VERSION 5.7 ;
  NOWIREEXTENSIONATPIN ON ;
  DIVIDERCHAR "/" ;
  BUSBITCHARS "[]" ;
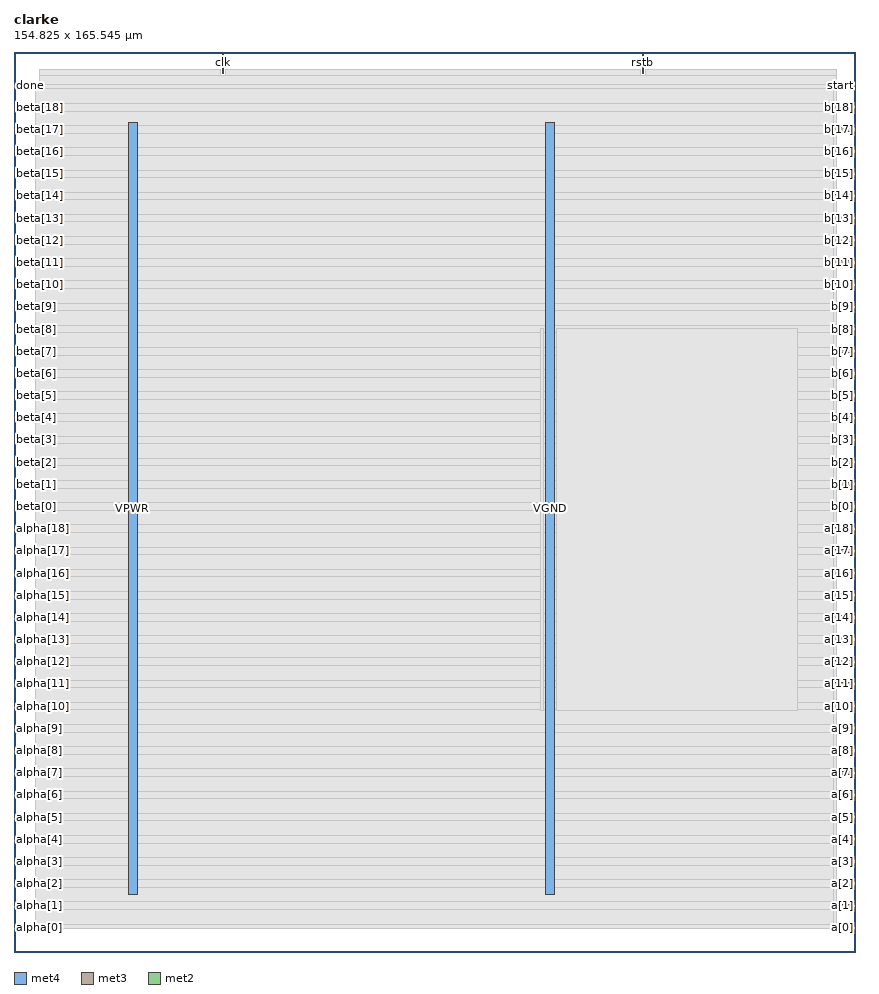
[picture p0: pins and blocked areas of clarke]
MACRO clarke
  CLASS BLOCK ;
  FOREIGN clarke ;
  ORIGIN 0.000 0.000 ;
  SIZE 154.825 BY 165.545 ;
  PIN VGND
    DIRECTION INOUT ;
    USE GROUND ;
    PORT
      LAYER met4 ;
        RECT 97.840 10.640 99.440 152.560 ;
    END
  END VGND
  PIN VPWR
    DIRECTION INOUT ;
    USE POWER ;
    PORT
      LAYER met4 ;
        RECT 21.040 10.640 22.640 152.560 ;
    END
  END VPWR
  PIN a[0]
    DIRECTION INPUT ;
    USE SIGNAL ;
    ANTENNAGATEAREA 0.213000 ;
    PORT
      LAYER met3 ;
        RECT 150.825 4.120 154.825 4.720 ;
    END
  END a[0]
  PIN a[10]
    DIRECTION INPUT ;
    USE SIGNAL ;
    ANTENNAGATEAREA 0.196500 ;
    PORT
      LAYER met3 ;
        RECT 150.825 44.920 154.825 45.520 ;
    END
  END a[10]
  PIN a[11]
    DIRECTION INPUT ;
    USE SIGNAL ;
    ANTENNAGATEAREA 0.213000 ;
    PORT
      LAYER met3 ;
        RECT 150.825 49.000 154.825 49.600 ;
    END
  END a[11]
  PIN a[12]
    DIRECTION INPUT ;
    USE SIGNAL ;
    ANTENNAGATEAREA 0.213000 ;
    PORT
      LAYER met3 ;
        RECT 150.825 53.080 154.825 53.680 ;
    END
  END a[12]
  PIN a[13]
    DIRECTION INPUT ;
    USE SIGNAL ;
    ANTENNAGATEAREA 0.159000 ;
    PORT
      LAYER met3 ;
        RECT 150.825 57.160 154.825 57.760 ;
    END
  END a[13]
  PIN a[14]
    DIRECTION INPUT ;
    USE SIGNAL ;
    ANTENNAGATEAREA 0.495000 ;
    PORT
      LAYER met3 ;
        RECT 150.825 61.240 154.825 61.840 ;
    END
  END a[14]
  PIN a[15]
    DIRECTION INPUT ;
    USE SIGNAL ;
    ANTENNAGATEAREA 0.196500 ;
    PORT
      LAYER met3 ;
        RECT 150.825 65.320 154.825 65.920 ;
    END
  END a[15]
  PIN a[16]
    DIRECTION INPUT ;
    USE SIGNAL ;
    ANTENNAGATEAREA 0.213000 ;
    PORT
      LAYER met3 ;
        RECT 150.825 69.400 154.825 70.000 ;
    END
  END a[16]
  PIN a[17]
    DIRECTION INPUT ;
    USE SIGNAL ;
    ANTENNAGATEAREA 0.159000 ;
    PORT
      LAYER met3 ;
        RECT 150.825 73.480 154.825 74.080 ;
    END
  END a[17]
  PIN a[18]
    DIRECTION INPUT ;
    USE SIGNAL ;
    ANTENNAGATEAREA 0.213000 ;
    PORT
      LAYER met3 ;
        RECT 150.825 77.560 154.825 78.160 ;
    END
  END a[18]
  PIN a[1]
    DIRECTION INPUT ;
    USE SIGNAL ;
    ANTENNAGATEAREA 0.213000 ;
    PORT
      LAYER met3 ;
        RECT 150.825 8.200 154.825 8.800 ;
    END
  END a[1]
  PIN a[2]
    DIRECTION INPUT ;
    USE SIGNAL ;
    ANTENNAGATEAREA 0.196500 ;
    PORT
      LAYER met3 ;
        RECT 150.825 12.280 154.825 12.880 ;
    END
  END a[2]
  PIN a[3]
    DIRECTION INPUT ;
    USE SIGNAL ;
    ANTENNAGATEAREA 0.213000 ;
    PORT
      LAYER met3 ;
        RECT 150.825 16.360 154.825 16.960 ;
    END
  END a[3]
  PIN a[4]
    DIRECTION INPUT ;
    USE SIGNAL ;
    ANTENNAGATEAREA 0.196500 ;
    PORT
      LAYER met3 ;
        RECT 150.825 20.440 154.825 21.040 ;
    END
  END a[4]
  PIN a[5]
    DIRECTION INPUT ;
    USE SIGNAL ;
    ANTENNAGATEAREA 0.196500 ;
    PORT
      LAYER met3 ;
        RECT 150.825 24.520 154.825 25.120 ;
    END
  END a[5]
  PIN a[6]
    DIRECTION INPUT ;
    USE SIGNAL ;
    ANTENNAGATEAREA 0.213000 ;
    PORT
      LAYER met3 ;
        RECT 150.825 28.600 154.825 29.200 ;
    END
  END a[6]
  PIN a[7]
    DIRECTION INPUT ;
    USE SIGNAL ;
    ANTENNAGATEAREA 0.213000 ;
    PORT
      LAYER met3 ;
        RECT 150.825 32.680 154.825 33.280 ;
    END
  END a[7]
  PIN a[8]
    DIRECTION INPUT ;
    USE SIGNAL ;
    ANTENNAGATEAREA 0.196500 ;
    PORT
      LAYER met3 ;
        RECT 150.825 36.760 154.825 37.360 ;
    END
  END a[8]
  PIN a[9]
    DIRECTION INPUT ;
    USE SIGNAL ;
    ANTENNAGATEAREA 0.213000 ;
    PORT
      LAYER met3 ;
        RECT 150.825 40.840 154.825 41.440 ;
    END
  END a[9]
  PIN alpha[0]
    DIRECTION OUTPUT ;
    USE SIGNAL ;
    ANTENNADIFFAREA 0.795200 ;
    PORT
      LAYER met3 ;
        RECT 0.000 4.120 4.000 4.720 ;
    END
  END alpha[0]
  PIN alpha[10]
    DIRECTION OUTPUT ;
    USE SIGNAL ;
    ANTENNADIFFAREA 0.795200 ;
    PORT
      LAYER met3 ;
        RECT 0.000 44.920 4.000 45.520 ;
    END
  END alpha[10]
  PIN alpha[11]
    DIRECTION OUTPUT ;
    USE SIGNAL ;
    ANTENNADIFFAREA 0.795200 ;
    PORT
      LAYER met3 ;
        RECT 0.000 49.000 4.000 49.600 ;
    END
  END alpha[11]
  PIN alpha[12]
    DIRECTION OUTPUT ;
    USE SIGNAL ;
    ANTENNADIFFAREA 0.795200 ;
    PORT
      LAYER met3 ;
        RECT 0.000 53.080 4.000 53.680 ;
    END
  END alpha[12]
  PIN alpha[13]
    DIRECTION OUTPUT ;
    USE SIGNAL ;
    ANTENNADIFFAREA 0.795200 ;
    PORT
      LAYER met3 ;
        RECT 0.000 57.160 4.000 57.760 ;
    END
  END alpha[13]
  PIN alpha[14]
    DIRECTION OUTPUT ;
    USE SIGNAL ;
    ANTENNADIFFAREA 0.795200 ;
    PORT
      LAYER met3 ;
        RECT 0.000 61.240 4.000 61.840 ;
    END
  END alpha[14]
  PIN alpha[15]
    DIRECTION OUTPUT ;
    USE SIGNAL ;
    ANTENNADIFFAREA 0.795200 ;
    PORT
      LAYER met3 ;
        RECT 0.000 65.320 4.000 65.920 ;
    END
  END alpha[15]
  PIN alpha[16]
    DIRECTION OUTPUT ;
    USE SIGNAL ;
    ANTENNADIFFAREA 0.795200 ;
    PORT
      LAYER met3 ;
        RECT 0.000 69.400 4.000 70.000 ;
    END
  END alpha[16]
  PIN alpha[17]
    DIRECTION OUTPUT ;
    USE SIGNAL ;
    ANTENNADIFFAREA 0.795200 ;
    PORT
      LAYER met3 ;
        RECT 0.000 73.480 4.000 74.080 ;
    END
  END alpha[17]
  PIN alpha[18]
    DIRECTION OUTPUT ;
    USE SIGNAL ;
    ANTENNADIFFAREA 0.795200 ;
    PORT
      LAYER met3 ;
        RECT 0.000 77.560 4.000 78.160 ;
    END
  END alpha[18]
  PIN alpha[1]
    DIRECTION OUTPUT ;
    USE SIGNAL ;
    ANTENNADIFFAREA 0.795200 ;
    PORT
      LAYER met3 ;
        RECT 0.000 8.200 4.000 8.800 ;
    END
  END alpha[1]
  PIN alpha[2]
    DIRECTION OUTPUT ;
    USE SIGNAL ;
    ANTENNADIFFAREA 0.795200 ;
    PORT
      LAYER met3 ;
        RECT 0.000 12.280 4.000 12.880 ;
    END
  END alpha[2]
  PIN alpha[3]
    DIRECTION OUTPUT ;
    USE SIGNAL ;
    ANTENNADIFFAREA 0.795200 ;
    PORT
      LAYER met3 ;
        RECT 0.000 16.360 4.000 16.960 ;
    END
  END alpha[3]
  PIN alpha[4]
    DIRECTION OUTPUT ;
    USE SIGNAL ;
    ANTENNADIFFAREA 0.795200 ;
    PORT
      LAYER met3 ;
        RECT 0.000 20.440 4.000 21.040 ;
    END
  END alpha[4]
  PIN alpha[5]
    DIRECTION OUTPUT ;
    USE SIGNAL ;
    ANTENNADIFFAREA 0.795200 ;
    PORT
      LAYER met3 ;
        RECT 0.000 24.520 4.000 25.120 ;
    END
  END alpha[5]
  PIN alpha[6]
    DIRECTION OUTPUT ;
    USE SIGNAL ;
    ANTENNADIFFAREA 0.795200 ;
    PORT
      LAYER met3 ;
        RECT 0.000 28.600 4.000 29.200 ;
    END
  END alpha[6]
  PIN alpha[7]
    DIRECTION OUTPUT ;
    USE SIGNAL ;
    ANTENNADIFFAREA 0.795200 ;
    PORT
      LAYER met3 ;
        RECT 0.000 32.680 4.000 33.280 ;
    END
  END alpha[7]
  PIN alpha[8]
    DIRECTION OUTPUT ;
    USE SIGNAL ;
    ANTENNADIFFAREA 0.795200 ;
    PORT
      LAYER met3 ;
        RECT 0.000 36.760 4.000 37.360 ;
    END
  END alpha[8]
  PIN alpha[9]
    DIRECTION OUTPUT ;
    USE SIGNAL ;
    ANTENNADIFFAREA 0.795200 ;
    PORT
      LAYER met3 ;
        RECT 0.000 40.840 4.000 41.440 ;
    END
  END alpha[9]
  PIN b[0]
    DIRECTION INPUT ;
    USE SIGNAL ;
    ANTENNAGATEAREA 0.126000 ;
    PORT
      LAYER met3 ;
        RECT 150.825 81.640 154.825 82.240 ;
    END
  END b[0]
  PIN b[10]
    DIRECTION INPUT ;
    USE SIGNAL ;
    ANTENNAGATEAREA 0.213000 ;
    PORT
      LAYER met3 ;
        RECT 150.825 122.440 154.825 123.040 ;
    END
  END b[10]
  PIN b[11]
    DIRECTION INPUT ;
    USE SIGNAL ;
    ANTENNAGATEAREA 0.196500 ;
    PORT
      LAYER met3 ;
        RECT 150.825 126.520 154.825 127.120 ;
    END
  END b[11]
  PIN b[12]
    DIRECTION INPUT ;
    USE SIGNAL ;
    ANTENNAGATEAREA 0.196500 ;
    PORT
      LAYER met3 ;
        RECT 150.825 130.600 154.825 131.200 ;
    END
  END b[12]
  PIN b[13]
    DIRECTION INPUT ;
    USE SIGNAL ;
    ANTENNAGATEAREA 0.196500 ;
    PORT
      LAYER met3 ;
        RECT 150.825 134.680 154.825 135.280 ;
    END
  END b[13]
  PIN b[14]
    DIRECTION INPUT ;
    USE SIGNAL ;
    ANTENNAGATEAREA 0.196500 ;
    PORT
      LAYER met3 ;
        RECT 150.825 138.760 154.825 139.360 ;
    END
  END b[14]
  PIN b[15]
    DIRECTION INPUT ;
    USE SIGNAL ;
    ANTENNAGATEAREA 0.196500 ;
    PORT
      LAYER met3 ;
        RECT 150.825 142.840 154.825 143.440 ;
    END
  END b[15]
  PIN b[16]
    DIRECTION INPUT ;
    USE SIGNAL ;
    ANTENNAGATEAREA 0.196500 ;
    PORT
      LAYER met3 ;
        RECT 150.825 146.920 154.825 147.520 ;
    END
  END b[16]
  PIN b[17]
    DIRECTION INPUT ;
    USE SIGNAL ;
    ANTENNAGATEAREA 0.196500 ;
    PORT
      LAYER met3 ;
        RECT 150.825 151.000 154.825 151.600 ;
    END
  END b[17]
  PIN b[18]
    DIRECTION INPUT ;
    USE SIGNAL ;
    ANTENNAGATEAREA 0.196500 ;
    PORT
      LAYER met3 ;
        RECT 150.825 155.080 154.825 155.680 ;
    END
  END b[18]
  PIN b[1]
    DIRECTION INPUT ;
    USE SIGNAL ;
    ANTENNAGATEAREA 0.196500 ;
    PORT
      LAYER met3 ;
        RECT 150.825 85.720 154.825 86.320 ;
    END
  END b[1]
  PIN b[2]
    DIRECTION INPUT ;
    USE SIGNAL ;
    ANTENNAGATEAREA 0.196500 ;
    PORT
      LAYER met3 ;
        RECT 150.825 89.800 154.825 90.400 ;
    END
  END b[2]
  PIN b[3]
    DIRECTION INPUT ;
    USE SIGNAL ;
    ANTENNAGATEAREA 0.196500 ;
    PORT
      LAYER met3 ;
        RECT 150.825 93.880 154.825 94.480 ;
    END
  END b[3]
  PIN b[4]
    DIRECTION INPUT ;
    USE SIGNAL ;
    ANTENNAGATEAREA 0.196500 ;
    PORT
      LAYER met3 ;
        RECT 150.825 97.960 154.825 98.560 ;
    END
  END b[4]
  PIN b[5]
    DIRECTION INPUT ;
    USE SIGNAL ;
    ANTENNAGATEAREA 0.196500 ;
    PORT
      LAYER met3 ;
        RECT 150.825 102.040 154.825 102.640 ;
    END
  END b[5]
  PIN b[6]
    DIRECTION INPUT ;
    USE SIGNAL ;
    ANTENNAGATEAREA 0.495000 ;
    PORT
      LAYER met3 ;
        RECT 150.825 106.120 154.825 106.720 ;
    END
  END b[6]
  PIN b[7]
    DIRECTION INPUT ;
    USE SIGNAL ;
    ANTENNAGATEAREA 0.196500 ;
    PORT
      LAYER met3 ;
        RECT 150.825 110.200 154.825 110.800 ;
    END
  END b[7]
  PIN b[8]
    DIRECTION INPUT ;
    USE SIGNAL ;
    ANTENNAGATEAREA 0.196500 ;
    PORT
      LAYER met3 ;
        RECT 150.825 114.280 154.825 114.880 ;
    END
  END b[8]
  PIN b[9]
    DIRECTION INPUT ;
    USE SIGNAL ;
    ANTENNAGATEAREA 0.196500 ;
    PORT
      LAYER met3 ;
        RECT 150.825 118.360 154.825 118.960 ;
    END
  END b[9]
  PIN beta[0]
    DIRECTION OUTPUT ;
    USE SIGNAL ;
    ANTENNADIFFAREA 0.795200 ;
    PORT
      LAYER met3 ;
        RECT 0.000 81.640 4.000 82.240 ;
    END
  END beta[0]
  PIN beta[10]
    DIRECTION OUTPUT ;
    USE SIGNAL ;
    ANTENNADIFFAREA 0.795200 ;
    PORT
      LAYER met3 ;
        RECT 0.000 122.440 4.000 123.040 ;
    END
  END beta[10]
  PIN beta[11]
    DIRECTION OUTPUT ;
    USE SIGNAL ;
    ANTENNADIFFAREA 0.795200 ;
    PORT
      LAYER met3 ;
        RECT 0.000 126.520 4.000 127.120 ;
    END
  END beta[11]
  PIN beta[12]
    DIRECTION OUTPUT ;
    USE SIGNAL ;
    ANTENNADIFFAREA 0.795200 ;
    PORT
      LAYER met3 ;
        RECT 0.000 130.600 4.000 131.200 ;
    END
  END beta[12]
  PIN beta[13]
    DIRECTION OUTPUT ;
    USE SIGNAL ;
    ANTENNADIFFAREA 0.795200 ;
    PORT
      LAYER met3 ;
        RECT 0.000 134.680 4.000 135.280 ;
    END
  END beta[13]
  PIN beta[14]
    DIRECTION OUTPUT ;
    USE SIGNAL ;
    ANTENNADIFFAREA 0.795200 ;
    PORT
      LAYER met3 ;
        RECT 0.000 138.760 4.000 139.360 ;
    END
  END beta[14]
  PIN beta[15]
    DIRECTION OUTPUT ;
    USE SIGNAL ;
    ANTENNADIFFAREA 0.795200 ;
    PORT
      LAYER met3 ;
        RECT 0.000 142.840 4.000 143.440 ;
    END
  END beta[15]
  PIN beta[16]
    DIRECTION OUTPUT ;
    USE SIGNAL ;
    ANTENNADIFFAREA 0.795200 ;
    PORT
      LAYER met3 ;
        RECT 0.000 146.920 4.000 147.520 ;
    END
  END beta[16]
  PIN beta[17]
    DIRECTION OUTPUT ;
    USE SIGNAL ;
    ANTENNADIFFAREA 0.795200 ;
    PORT
      LAYER met3 ;
        RECT 0.000 151.000 4.000 151.600 ;
    END
  END beta[17]
  PIN beta[18]
    DIRECTION OUTPUT ;
    USE SIGNAL ;
    ANTENNADIFFAREA 0.795200 ;
    PORT
      LAYER met3 ;
        RECT 0.000 155.080 4.000 155.680 ;
    END
  END beta[18]
  PIN beta[1]
    DIRECTION OUTPUT ;
    USE SIGNAL ;
    ANTENNADIFFAREA 0.795200 ;
    PORT
      LAYER met3 ;
        RECT 0.000 85.720 4.000 86.320 ;
    END
  END beta[1]
  PIN beta[2]
    DIRECTION OUTPUT ;
    USE SIGNAL ;
    ANTENNADIFFAREA 0.795200 ;
    PORT
      LAYER met3 ;
        RECT 0.000 89.800 4.000 90.400 ;
    END
  END beta[2]
  PIN beta[3]
    DIRECTION OUTPUT ;
    USE SIGNAL ;
    ANTENNADIFFAREA 0.795200 ;
    PORT
      LAYER met3 ;
        RECT 0.000 93.880 4.000 94.480 ;
    END
  END beta[3]
  PIN beta[4]
    DIRECTION OUTPUT ;
    USE SIGNAL ;
    ANTENNADIFFAREA 0.795200 ;
    PORT
      LAYER met3 ;
        RECT 0.000 97.960 4.000 98.560 ;
    END
  END beta[4]
  PIN beta[5]
    DIRECTION OUTPUT ;
    USE SIGNAL ;
    ANTENNADIFFAREA 0.795200 ;
    PORT
      LAYER met3 ;
        RECT 0.000 102.040 4.000 102.640 ;
    END
  END beta[5]
  PIN beta[6]
    DIRECTION OUTPUT ;
    USE SIGNAL ;
    ANTENNADIFFAREA 0.795200 ;
    PORT
      LAYER met3 ;
        RECT 0.000 106.120 4.000 106.720 ;
    END
  END beta[6]
  PIN beta[7]
    DIRECTION OUTPUT ;
    USE SIGNAL ;
    ANTENNADIFFAREA 0.795200 ;
    PORT
      LAYER met3 ;
        RECT 0.000 110.200 4.000 110.800 ;
    END
  END beta[7]
  PIN beta[8]
    DIRECTION OUTPUT ;
    USE SIGNAL ;
    ANTENNADIFFAREA 0.795200 ;
    PORT
      LAYER met3 ;
        RECT 0.000 114.280 4.000 114.880 ;
    END
  END beta[8]
  PIN beta[9]
    DIRECTION OUTPUT ;
    USE SIGNAL ;
    ANTENNADIFFAREA 0.795200 ;
    PORT
      LAYER met3 ;
        RECT 0.000 118.360 4.000 118.960 ;
    END
  END beta[9]
  PIN clk
    DIRECTION INPUT ;
    USE SIGNAL ;
    ANTENNAGATEAREA 0.852000 ;
    PORT
      LAYER met2 ;
        RECT 38.270 161.545 38.550 165.545 ;
    END
  END clk
  PIN done
    DIRECTION OUTPUT ;
    USE SIGNAL ;
    ANTENNADIFFAREA 0.795200 ;
    PORT
      LAYER met3 ;
        RECT 0.000 159.160 4.000 159.760 ;
    END
  END done
  PIN rstb
    DIRECTION INPUT ;
    USE SIGNAL ;
    ANTENNAGATEAREA 0.213000 ;
    PORT
      LAYER met2 ;
        RECT 115.550 161.545 115.830 165.545 ;
    END
  END rstb
  PIN start
    DIRECTION INPUT ;
    USE SIGNAL ;
    ANTENNAGATEAREA 0.159000 ;
    PORT
      LAYER met3 ;
        RECT 150.825 159.160 154.825 159.760 ;
    END
  END start
  OBS
      LAYER li1 ;
        RECT 5.520 10.795 149.040 152.405 ;
      LAYER met1 ;
        RECT 4.670 10.240 151.270 152.560 ;
      LAYER met2 ;
        RECT 4.690 161.265 37.990 162.250 ;
        RECT 38.830 161.265 115.270 162.250 ;
        RECT 116.110 161.265 151.240 162.250 ;
        RECT 4.690 4.235 151.240 161.265 ;
      LAYER met3 ;
        RECT 4.400 158.760 150.425 159.625 ;
        RECT 3.990 156.080 150.825 158.760 ;
        RECT 4.400 154.680 150.425 156.080 ;
        RECT 3.990 152.000 150.825 154.680 ;
        RECT 4.400 150.600 150.425 152.000 ;
        RECT 3.990 147.920 150.825 150.600 ;
        RECT 4.400 146.520 150.425 147.920 ;
        RECT 3.990 143.840 150.825 146.520 ;
        RECT 4.400 142.440 150.425 143.840 ;
        RECT 3.990 139.760 150.825 142.440 ;
        RECT 4.400 138.360 150.425 139.760 ;
        RECT 3.990 135.680 150.825 138.360 ;
        RECT 4.400 134.280 150.425 135.680 ;
        RECT 3.990 131.600 150.825 134.280 ;
        RECT 4.400 130.200 150.425 131.600 ;
        RECT 3.990 127.520 150.825 130.200 ;
        RECT 4.400 126.120 150.425 127.520 ;
        RECT 3.990 123.440 150.825 126.120 ;
        RECT 4.400 122.040 150.425 123.440 ;
        RECT 3.990 119.360 150.825 122.040 ;
        RECT 4.400 117.960 150.425 119.360 ;
        RECT 3.990 115.280 150.825 117.960 ;
        RECT 4.400 113.880 150.425 115.280 ;
        RECT 3.990 111.200 150.825 113.880 ;
        RECT 4.400 109.800 150.425 111.200 ;
        RECT 3.990 107.120 150.825 109.800 ;
        RECT 4.400 105.720 150.425 107.120 ;
        RECT 3.990 103.040 150.825 105.720 ;
        RECT 4.400 101.640 150.425 103.040 ;
        RECT 3.990 98.960 150.825 101.640 ;
        RECT 4.400 97.560 150.425 98.960 ;
        RECT 3.990 94.880 150.825 97.560 ;
        RECT 4.400 93.480 150.425 94.880 ;
        RECT 3.990 90.800 150.825 93.480 ;
        RECT 4.400 89.400 150.425 90.800 ;
        RECT 3.990 86.720 150.825 89.400 ;
        RECT 4.400 85.320 150.425 86.720 ;
        RECT 3.990 82.640 150.825 85.320 ;
        RECT 4.400 81.240 150.425 82.640 ;
        RECT 3.990 78.560 150.825 81.240 ;
        RECT 4.400 77.160 150.425 78.560 ;
        RECT 3.990 74.480 150.825 77.160 ;
        RECT 4.400 73.080 150.425 74.480 ;
        RECT 3.990 70.400 150.825 73.080 ;
        RECT 4.400 69.000 150.425 70.400 ;
        RECT 3.990 66.320 150.825 69.000 ;
        RECT 4.400 64.920 150.425 66.320 ;
        RECT 3.990 62.240 150.825 64.920 ;
        RECT 4.400 60.840 150.425 62.240 ;
        RECT 3.990 58.160 150.825 60.840 ;
        RECT 4.400 56.760 150.425 58.160 ;
        RECT 3.990 54.080 150.825 56.760 ;
        RECT 4.400 52.680 150.425 54.080 ;
        RECT 3.990 50.000 150.825 52.680 ;
        RECT 4.400 48.600 150.425 50.000 ;
        RECT 3.990 45.920 150.825 48.600 ;
        RECT 4.400 44.520 150.425 45.920 ;
        RECT 3.990 41.840 150.825 44.520 ;
        RECT 4.400 40.440 150.425 41.840 ;
        RECT 3.990 37.760 150.825 40.440 ;
        RECT 4.400 36.360 150.425 37.760 ;
        RECT 3.990 33.680 150.825 36.360 ;
        RECT 4.400 32.280 150.425 33.680 ;
        RECT 3.990 29.600 150.825 32.280 ;
        RECT 4.400 28.200 150.425 29.600 ;
        RECT 3.990 25.520 150.825 28.200 ;
        RECT 4.400 24.120 150.425 25.520 ;
        RECT 3.990 21.440 150.825 24.120 ;
        RECT 4.400 20.040 150.425 21.440 ;
        RECT 3.990 17.360 150.825 20.040 ;
        RECT 4.400 15.960 150.425 17.360 ;
        RECT 3.990 13.280 150.825 15.960 ;
        RECT 4.400 11.880 150.425 13.280 ;
        RECT 3.990 9.200 150.825 11.880 ;
        RECT 4.400 7.800 150.425 9.200 ;
        RECT 3.990 5.120 150.825 7.800 ;
        RECT 4.400 4.255 150.425 5.120 ;
      LAYER met4 ;
        RECT 96.895 44.375 97.440 114.745 ;
        RECT 99.840 44.375 144.145 114.745 ;
  END
END clarke
END LIBRARY

